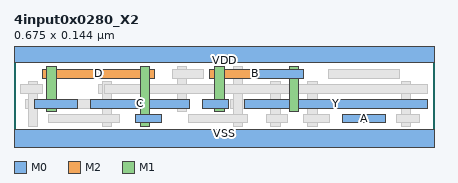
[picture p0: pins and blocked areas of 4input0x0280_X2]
MACRO 4input0x0280_X2
  CLASS CORE ;
  ORIGIN 0 0 ;
  FOREIGN 4input0x0280_X2 0 0 ;
  SIZE 0.6750 BY 0.1440 ;
  SYMMETRY X Y ;
  SITE coresite ;
  PIN A
    DIRECTION INPUT ;
    USE SIGNAL ;
    PORT
      LAYER M0 ;
        RECT 0.5280 0.0290 0.5970 0.0430 ;
    END
  END A
  PIN B
    DIRECTION INPUT ;
    USE SIGNAL ;
    PORT
      LAYER M2 ;
        RECT 0.3150 0.1010 0.4620 0.1150 ;
      LAYER M1 ;
        RECT 0.3225 0.0480 0.3375 0.1200 ;
        RECT 0.4425 0.0480 0.4575 0.1200 ;
      LAYER M0 ;
        RECT 0.3930 0.1010 0.4650 0.1150 ;
        RECT 0.3030 0.0530 0.3450 0.0670 ;
    END
  END B
  PIN C
    DIRECTION INPUT ;
    USE SIGNAL ;
    PORT
      LAYER M0 ;
        RECT 0.1230 0.0530 0.2820 0.0670 ;
    END
  END C
  PIN D
    DIRECTION INPUT ;
    USE SIGNAL ;
    PORT
      LAYER M2 ;
        RECT 0.0450 0.1010 0.2250 0.1150 ;
      LAYER M1 ;
        RECT 0.0525 0.0480 0.0675 0.1200 ;
        RECT 0.2025 0.0240 0.2175 0.1200 ;
      LAYER M0 ;
        RECT 0.1950 0.0290 0.2370 0.0430 ;
        RECT 0.0330 0.0530 0.1020 0.0670 ;
    END
  END D
  PIN Y
    DIRECTION OUTPUT ;
    USE SIGNAL ;
    PORT
      LAYER M0 ;
        RECT 0.3705 0.0530 0.6645 0.0670 ;
    END
  END Y
  PIN VDD
    DIRECTION INOUT ;
    USE POWER ;
    SHAPE ABUTMENT ;
    PORT
      LAYER M0 ;
        RECT 0.0000 0.1260 0.6750 0.1620 ;
    END
  END VDD
  PIN VSS
    DIRECTION INOUT ;
    USE GROUND ;
    SHAPE ABUTMENT ;
    PORT
      LAYER M0 ;
        RECT 0.0000 -0.0180 0.6750 0.0180 ;
    END
  END VSS
  OBS
    LAYER V1 ;
      RECT 0.0230 0.0530 0.0370 0.0670 ;
      RECT 0.2630 0.0530 0.2770 0.0670 ;
      RECT 0.3530 0.0530 0.3670 0.0670 ;
      RECT 0.4730 0.0530 0.4870 0.0670 ;
      RECT 0.6230 0.0530 0.6370 0.0670 ;
      RECT 0.0530 0.1010 0.0670 0.1150 ;
      RECT 0.2030 0.1010 0.2170 0.1150 ;
      RECT 0.1430 0.0770 0.1570 0.0910 ;
      RECT 0.4130 0.0770 0.4270 0.0910 ;
      RECT 0.3230 0.1010 0.3370 0.1150 ;
      RECT 0.4430 0.1010 0.4570 0.1150 ;
    LAYER M2 ;
      RECT 0.0180 0.0530 0.2820 0.0670 ;
      RECT 0.3480 0.0530 0.6420 0.0670 ;
      RECT 0.1350 0.0770 0.4320 0.0910 ;
    LAYER V0 ;
      RECT 0.0230 0.0770 0.0370 0.0910 ;
      RECT 0.2630 0.1010 0.2770 0.1150 ;
      RECT 0.3530 0.1010 0.3670 0.1150 ;
      RECT 0.3530 0.0290 0.3670 0.0430 ;
      RECT 0.4730 0.0290 0.4870 0.0430 ;
      RECT 0.6230 0.0290 0.6370 0.0430 ;
      RECT 0.0530 0.0530 0.0670 0.0670 ;
      RECT 0.2030 0.0290 0.2170 0.0430 ;
      RECT 0.1430 0.0290 0.1570 0.0430 ;
      RECT 0.4130 0.0290 0.4270 0.0430 ;
      RECT 0.3230 0.0530 0.3370 0.0670 ;
      RECT 0.4430 0.1010 0.4570 0.1150 ;
    LAYER M1 ;
      RECT 0.0225 0.0240 0.0375 0.0960 ;
      RECT 0.1425 0.0240 0.1575 0.0960 ;
      RECT 0.4125 0.0240 0.4275 0.0960 ;
      RECT 0.4725 0.0240 0.4875 0.0960 ;
      RECT 0.6225 0.0240 0.6375 0.0960 ;
      RECT 0.2625 0.0480 0.2775 0.1200 ;
      RECT 0.3525 0.0240 0.3675 0.1200 ;
    LAYER M0 ;
      RECT 0.0555 0.0290 0.1695 0.0430 ;
      RECT 0.2805 0.0290 0.3750 0.0430 ;
      RECT 0.4050 0.0290 0.4395 0.0430 ;
      RECT 0.4650 0.0290 0.5070 0.0430 ;
      RECT 0.6150 0.0290 0.6525 0.0430 ;
      RECT 0.0105 0.0770 0.0450 0.0910 ;
      RECT 0.1455 0.0770 0.6645 0.0910 ;
      RECT 0.1005 0.1010 0.2145 0.1150 ;
      RECT 0.2550 0.1010 0.3045 0.1150 ;
      RECT 0.3255 0.1010 0.3750 0.1150 ;
      RECT 0.5055 0.1010 0.6195 0.1150 ;
  END
END 4input0x0280_X2
